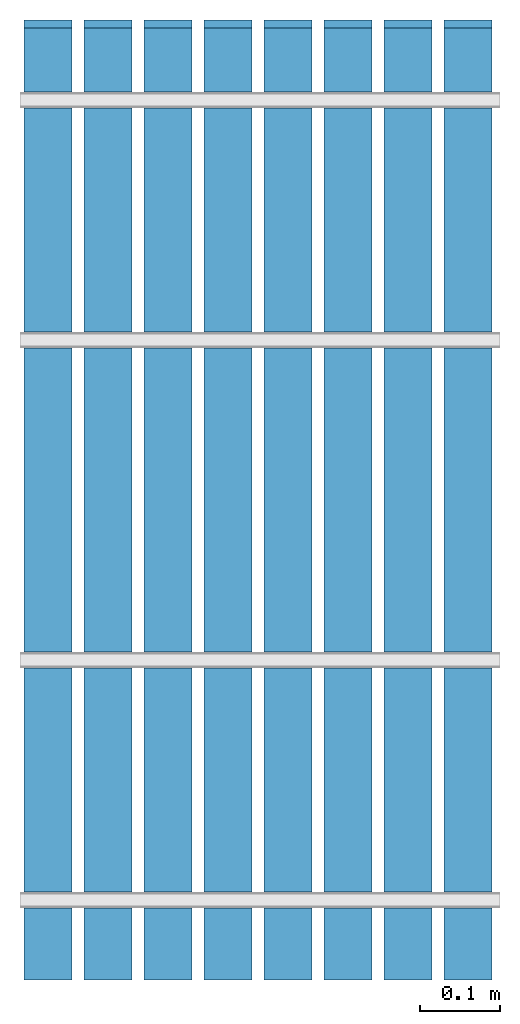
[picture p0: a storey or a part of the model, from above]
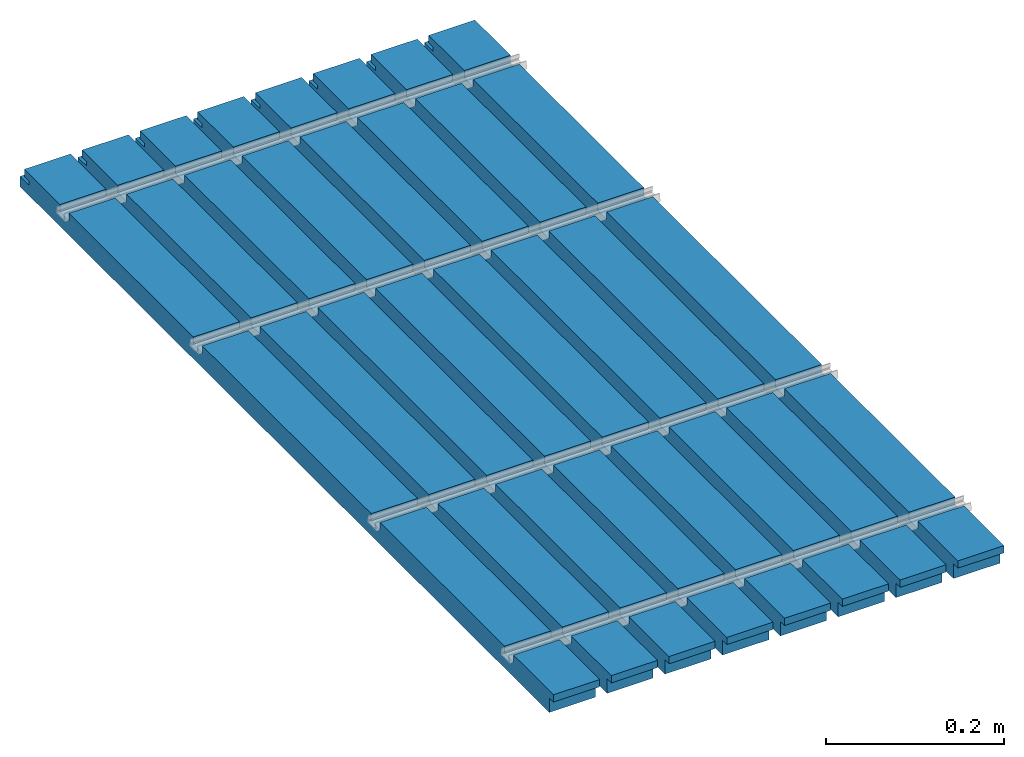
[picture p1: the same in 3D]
Properties of the parts of a building model (IFC2X3)

# File
Description: ViewDefinition [CoordinationView_V2.0], Option [Drawing Scale: 2.000000], Option [Global Unique Identifiers (GUID): Keep existing], Option [Elements to export: Selected elements only], Option [Partial Structure Display: Entire Model], Option [IFC Domain: All], Option [Structural Function: All Elements], Option [Convert Grid elements: On], Option [Convert IFC Annotations and ARCHICAD 2D elements: On], Option [Convert 2D symbols of Doors and Windows: On], Option [Explode Composite and Complex Profile elements into parts: Off], Option [Export geometries that Participates in Collision Detection only: On], Option [Multi-skin complex geometries: Building element parts], Option [Elements in Solid Element Operations: Extruded/revolved], Option [Elements with junctions: Extruded/revolved without junctions], Option [Slabs with slanted edge(s): Extruded], Option [Use legacy geometric methods as in Coordination View 1.0: Off], Option [IFC Site Geometry: As boundary representation (BRep)], Option [IFC Site Location: At Project Origin], Option [Properties To Export: All properties], Option [Space containment: Off], Option [Bounding Box: Off], Option [Geometry to type objects: Off], Option [Element Properties: Off], Option [Element Parameters: Off], Option [IFC Base Quantities: Off], Option [Window Door Lining and Panel Parameters: On], Option [IFC Space boundaries: Off], Option [ARCHICAD Zone Categories as IFC Space classification data: Off]
File name: H:\Blade IFC Files\ICF Group UnikaVaev\UV3060- 8 x 1200.ifc
Time: 2017-07-26T14:11:35
Author: Architect
Organization: Building Designer Office
Written by: The EXPRESS Data Manager Version 5.02.0100.09 : 26 Sep 2013
Made in: IFC file generated by GRAPHISOFT ARCHICAD-64 20.0.0 AUS FULL Windows version (IFC2x3 add-on version: 5025 AUS FULL).
Authorization: The authorising person

# IfcSite, Site
RefLatitude: -33, -52, 0, 0; RefLongitude: 151, 13, 0, 0; RefElevation: 0 mm

# IfcBuildingStorey, GROUND
In: Building
Elevation: 0 mm

# IfcBeam: 15MM GRID 20 x 10 (4)
In: GROUND
Material: Brick - Internal Wall
AC_Pset_RenovationAndPhasing - Renovation Status: New
Pset_BeamCommon - LoadBearing: yes; IsExternal: no; Reference: 15MM GRID 20 x 10

# IfcWallStandardCase: Timber 60 (8)
In: GROUND
Material: Timber 60 mm
AC_Pset_RenovationAndPhasing - Renovation Status: New
Pset_WallCommon - LoadBearing: yes; IsExternal: yes
